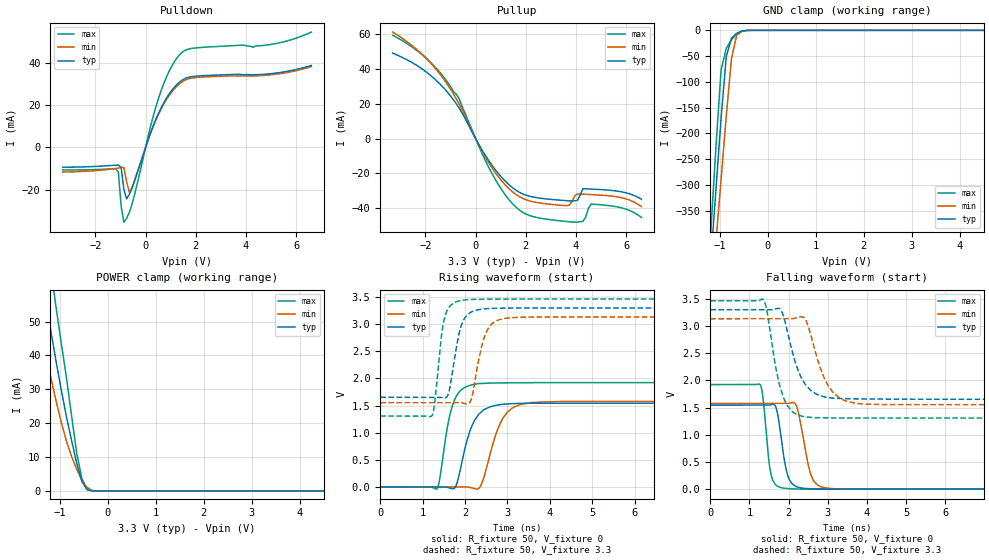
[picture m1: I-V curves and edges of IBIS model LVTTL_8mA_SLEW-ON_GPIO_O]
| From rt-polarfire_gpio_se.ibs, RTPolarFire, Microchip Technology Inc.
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|   Model LVTTL_8mA_SLEW-ON_GPIO_O
[Model]   LVTTL_8mA_SLEW-ON_GPIO_O
Model_type   Output
Polarity   Non-Inverting
Enable   Active-High
Vmeas =   1.65
Cref =   5p
Rref =   1M
|   typ   min   max
C_comp_pullup   2.605e-12   2.605e-12   2.76e-12
C_comp_pulldown  2.605e-12   2.605e-12   2.76e-12
[Temperature Range]  25C   125C   -55C
[Voltage Range]  3.3   3.135   3.465
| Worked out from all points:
|   slope of the pulldown table from 0 to 0.495 V, typ, clamps not added: 31.7 ohm
|   slope of the pullup table from 0 to 0.495 V, typ, clamps not added: 41.2 ohm
|   GND clamp passes 1 mA (typ) near -0.51 V on its own axis
|   POWER clamp passes 1 mA (typ) near -0.46 V on its own axis
|   rising waveform, R_fixture 50, V_fixture 0: 20-80 % time 346ps typ, 395ps min, 271ps max; typ from 0 V to 1.55 V
|   rising waveform, R_fixture 50, V_fixture 3.3: 20-80 % time 236ps typ, 265ps min, 183ps max; typ from 1.65 V to 3.3 V
|   falling waveform, R_fixture 50, V_fixture 0: 20-80 % time 203ps typ, 256ps min, 156ps max; typ from 1.55 V to 0 V
|   falling waveform, R_fixture 50, V_fixture 3.3: 20-80 % time 432ps typ, 471ps min, 341ps max; typ from 3.3 V to 1.65 V
[GND Clamp]
| Voltage   I(typ)   I(min)   I(max)
-3.3V     -3.213A    -2.953A    -3.676A
-1.191V   -450mA     -534.3mA   -393.2mA
-1.083V   -310.2mA   -411.6mA   -227.5mA
-974.5mV  -170.4mA   -288.9mA   -76.97mA
-866.2mV  -50.48mA   -166.3mA   -34.78mA
-758mV    -15.08mA   -54.7mA    -18.33mA
-649.7mV  -5.883mA   -9.683mA   -6.874mA
-541.4mV  -1.389mA   -1.864mA   -1.426mA
-324.8mV  -3.553uA   -16.68uA   -1.172uA
6.6V      0A         0A         0A
[POWER Clamp]
| Voltage   I(typ)   I(min)   I(max)
-3.3V     320.3mA    256.6mA    387.1mA
-1.624V   89.11mA    65.97mA    116.9mA
-1.408V   67.23mA    48.87mA    90.32mA
-1.299V   57.08mA    41.04mA    77.84mA
-1.191V   47.51mA    33.68mA    65.79mA
-1.083V   38.51mA    26.79mA    54.52mA
-866.2mV  22.14mA    14.9mA     33.75mA
-649.7mV  8.213mA    6.429mA    11.19mA
-541.4mV  2.791mA    3.18mA     3.642mA
-433.1mV  359.8uA    981.3uA    499.4uA
-216.6mV  159.8nA    8.88uA     59.07nA
6.6V      0A         0A         0A
[Pullup]
| Voltage   I(typ)   I(min)   I(max)
-3.3V     49.01mA    61.08mA    59.23mA
-1.841V   36.8mA     44.17mA    44.41mA
-758mV    19.77mA    22.59mA    25.23mA
618.8mV   -14.64mA   -16.01mA   -19.11mA
1.238V    -25.28mA   -27.44mA   -33.37mA
1.753V    -30.9mA    -33.39mA   -41.12mA
3.625V    -35.67mA   -38.52mA   -47.62mA
4.058V    -35.49mA   -31.76mA   -47.93mA
4.275V    -28.78mA   -31.92mA   -47.51mA
4.599V    -29mA      -32.17mA   -37.61mA
5.79V     -30.53mA   -33.88mA   -39.68mA
6.6V      -34.85mA   -39.01mA   -45.28mA
[Pulldown]
| Voltage   I(typ)   I(min)   I(max)
-3.3V     -9.313mA   -11.56mA   -10.59mA
-1.191V   -8.379mA   -9.941mA   -9.988mA
-1.083V   -8.301mA   -9.731mA   -11.63mA
-974.5mV  -9.371mA   -9.502mA   -27.6mA
-866.2mV  -19.57mA   -9.359mA   -35.26mA
-758mV    -24.21mA   -15.94mA   -33.52mA
-649.7mV  -22.21mA   -21.08mA   -30.78mA
515.6mV   16.17mA    15.64mA    23.21mA
1.341V    30.74mA    29.91mA    43.59mA
1.959V    33.59mA    32.92mA    46.9mA
5.141V    35.03mA    34.49mA    48.92mA
6.6V      38.71mA    38.17mA    54.44mA
[Ramp]
dV/dt_r   0.927346/0.346344n  0.946255/0.395245n  1.15407/0.270643n
dV/dt_f   0.987567/0.432188n  0.948706/0.471307n  1.29419/0.341378n
R_load = 50
[Rising Waveform]
R_fixture = 50
V_fixture = 0
V_fixture_min = 0
V_fixture_max = 0
| Time   V(typ)   V(min)   V(max)
0s        62.35nV    86.47nV    169.2nV
1.341ns   927uV      524.7uV    -31.51mV
1.603ns   -11.81mV   627.2uV    1.19V
1.712ns   -34.88mV   669.8uV    1.527V
1.801ns   52.34mV    704.6uV    1.682V
2.192ns   1.177V     -24.92mV   1.891V
2.379ns   1.382V     37.41mV    1.908V
2.906ns   1.526V     1.285V     1.92V
3.367ns   1.542V     1.531V     1.923V
10ns      1.546V     1.577V     1.923V
[Rising Waveform]
R_fixture = 50
V_fixture = 3.3
V_fixture_min = 3.135
V_fixture_max = 3.465
| Time   V(typ)   V(min)   V(max)
0s        1.654V     1.554V     1.308V
1.219ns   1.654V     1.554V     1.316V
1.277ns   1.654V     1.554V     1.511V
1.509ns   1.64V      1.555V     3.094V
1.624ns   1.77V      1.555V     3.316V
1.808ns   2.634V     1.555V     3.421V
2.128ns   3.218V     1.582V     3.458V
2.493ns   3.287V     2.843V     3.464V
2.888ns   3.298V     3.101V     3.465V
10ns      3.3V       3.135V     3.465V
[Falling Waveform]
R_fixture = 50
V_fixture = 0
V_fixture_min = 0
V_fixture_max = 0
| Time   V(typ)   V(min)   V(max)
0s        1.546V     1.577V     1.923V
1.278ns   1.546V     1.577V     1.918V
1.559ns   1.554V     1.577V     247.9mV
1.677ns   1.508V     1.577V     75.12mV
1.795ns   1.029V     1.577V     29.68mV
2.088ns   100.2mV    1.594V     5.404mV
2.229ns   38.44mV    1.47V      2.652mV
2.57ns    6.707mV    265.9mV    552.5uV
2.836ns   2.188mV    41.34mV    532.7uV
10ns      749.4nV    5.079uV    113.4nV
[Falling Waveform]
R_fixture = 50
V_fixture = 3.3
V_fixture_min = 3.135
V_fixture_max = 3.465
| Time   V(typ)   V(min)   V(max)
0s        3.3V       3.135V     3.465V
1.362ns   3.299V     3.134V     3.482V
1.449ns   3.299V     3.134V     3.274V
1.723ns   3.328V     3.134V     2.056V
1.856ns   3.211V     3.134V     1.707V
2.339ns   2.035V     3.171V     1.341V
2.468ns   1.893V     3.063V     1.327V
3ns       1.687V     1.917V     1.309V
3.492ns   1.663V     1.613V     1.309V
10ns      1.654V     1.554V     1.308V
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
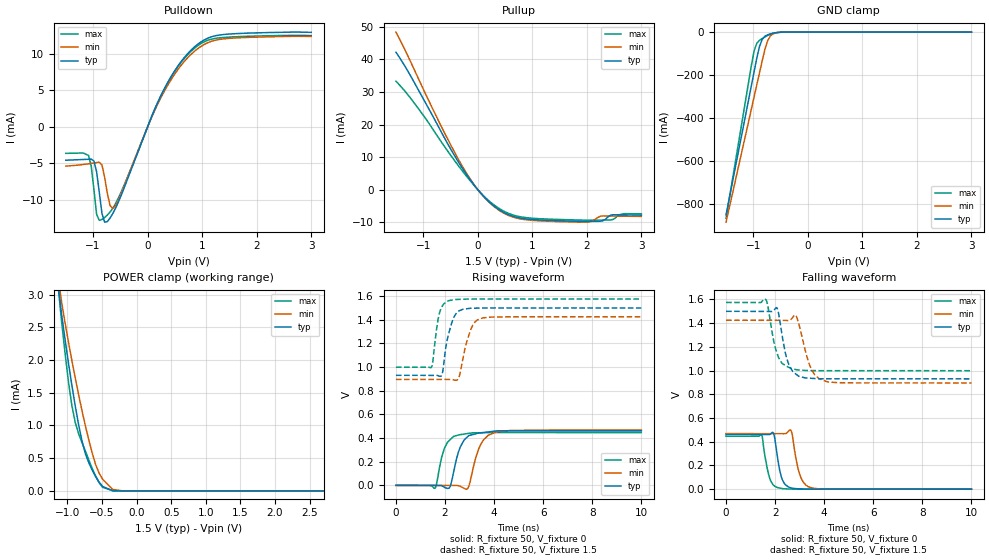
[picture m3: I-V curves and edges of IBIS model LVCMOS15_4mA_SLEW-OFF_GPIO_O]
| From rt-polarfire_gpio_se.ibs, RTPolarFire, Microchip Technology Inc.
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|   Model LVCMOS15_4mA_SLEW-OFF_GPIO_O
[Model]   LVCMOS15_4mA_SLEW-OFF_GPIO_O
Model_type   Output
Polarity   Non-Inverting
Enable   Active-High
Vmeas =   0.75
Cref =   5p
Rref =   1M
|   typ   min   max
C_comp_pullup   2.605e-12   2.605e-12   2.76e-12
C_comp_pulldown  2.605e-12   2.605e-12   2.76e-12
[Temperature Range]  25C   125C   -55C
[Voltage Range]  1.5   1.425   1.575
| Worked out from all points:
|   slope of the pulldown table from 0 to 0.225 V, typ, clamps not added: 56.6 ohm
|   slope of the pullup table from 0 to 0.225 V, typ, clamps not added: 56.5 ohm
|   GND clamp passes 1 mA (typ) near -0.52 V on its own axis
|   POWER clamp passes 1 mA (typ) near -0.84 V on its own axis
|   rising waveform, R_fixture 50, V_fixture 0: 20-80 % time 409ps typ, 449ps min, 359ps max; typ from 0 V to 0.461 V
|   rising waveform, R_fixture 50, V_fixture 1.5: 20-80 % time 336ps typ, 390ps min, 240ps max; typ from 0.93 V to 1.5 V
|   falling waveform, R_fixture 50, V_fixture 0: 20-80 % time 246ps typ, 301ps min, 255ps max; typ from 0.461 V to 0 V
|   falling waveform, R_fixture 50, V_fixture 1.5: 20-80 % time 356ps typ, 447ps min, 362ps max; typ from 1.5 V to 0.93 V
[GND Clamp]
| Voltage   I(typ)   I(min)   I(max)
-1.5V     -849.7mA   -884.3mA   -866.2mA
-1.034V   -246.6mA   -355.8mA   -152.2mA
-984.4mV  -183.1mA   -300.1mA   -86.85mA
-935.2mV  -119.9mA   -244.3mA   -51.18mA
-885.9mV  -66.33mA   -188.6mA   -38.3mA
-836.7mV  -33.59mA   -133mA     -29.88mA
-787.5mV  -19.44mA   -80.26mA   -22.39mA
-738.3mV  -12.87mA   -40.96mA   -15.82mA
-689.1mV  -8.545mA   -18.39mA   -10.35mA
-590.6mV  -2.947mA   -3.965mA   -3.201mA
-393.7mV  -37.64uA   -97.05uA   -25.54uA
3V        0A         0A         0A
[POWER Clamp]
| Voltage   I(typ)   I(min)   I(max)
-1.5V     10.9mA     9.514mA    12.44mA
-1.181V   3.55mA     3.619mA    3.648mA
-1.083V   2.694mA    2.882mA    2.583mA
-984.4mV  1.956mA    2.276mA    1.667mA
-935.2mV  1.615mA    1.995mA    1.306mA
-885.9mV  1.297mA    1.724mA    1.047mA
-738.3mV  562.1uA    988.5uA    604.8uA
-590.6mV  217.4uA    399.3uA    223.5uA
-492.2mV  69.4uA     180.6uA    55.95uA
-344.5mV  1.546uA    22.26uA    2.965uA
-196.9mV  138.9nA    703.2nA    3.319nA
3V        0A         0A         0A
[Pullup]
| Voltage   I(typ)   I(min)   I(max)
-1.5V     42.22mA    48.41mA    33.32mA
-1.083V   30.48mA    33.93mA    24.78mA
-344.5mV  8.198mA    8.976mA    7.117mA
0V        -138.7nA   6.972uA    19.76uA
328.1mV   -5.411mA   -5.582mA   -5.058mA
656.2mV   -8.252mA   -8.491mA   -7.836mA
1.078V    -9.265mA   -9.527mA   -8.873mA
1.992V    -9.771mA   -9.982mA   -9.385mA
2.238V    -9.714mA   -8.228mA   -9.368mA
2.435V    -7.83mA    -8.102mA   -9.304mA
2.681V    -7.759mA   -8.159mA   -7.381mA
3V        -7.819mA   -8.223mA   -7.437mA
[Pulldown]
| Voltage   I(typ)   I(min)   I(max)
-1.5V     -4.58mA    -5.384mA   -3.635mA
-1.083V   -4.447mA   -5.071mA   -3.924mA
-984.4mV  -4.677mA   -4.965mA   -8.591mA
-935.2mV  -6.154mA   -4.907mA   -12.01mA
-836.7mV  -11.89mA   -5.226mA   -12.7mA
-787.5mV  -13.08mA   -6.95mA    -12.44mA
-689.1mV  -12.52mA   -10.78mA   -11.69mA
-590.6mV  -11.2mA    -10.83mA   -10.57mA
234.4mV   4.121mA    3.858mA    4.109mA
843.8mV   10.86mA    10.26mA    10.68mA
1.359V    12.63mA    12.03mA    12.24mA
3V        12.96mA    12.41mA    12.52mA
[Ramp]
dV/dt_r   0.276675/0.408785n  0.281298/0.448932n  0.26773/0.358544n
dV/dt_f   0.341778/0.356073n  0.317434/0.446663n  0.345465/0.361764n
R_load = 50
[Rising Waveform]
R_fixture = 50
V_fixture = 0
V_fixture_min = 0
V_fixture_max = 0
| Time   V(typ)   V(min)   V(max)
0s        19.64nV    51.11nV    26.19nV
1.589ns   -750uV     -478.5uV   -25.07mV
1.871ns   -3.997mV   -563.5uV   242.9mV
2.18ns    -19.84mV   -656.5uV   380.3mV
2.599ns   311.7mV    -6.501mV   428.1mV
2.934ns   413.7mV    -23.14mV   438.6mV
3.439ns   443.8mV    340mV      444.7mV
3.771ns   452mV      425mV      445.6mV
4.102ns   460.3mV    452mV      446.5mV
10ns      461.1mV    468.8mV    446.2mV
[Rising Waveform]
R_fixture = 50
V_fixture = 1.5
V_fixture_min = 1.425
V_fixture_max = 1.575
| Time   V(typ)   V(min)   V(max)
0s        930.4mV    895.9mV    999.2mV
1.439ns   929.7mV    895.4mV    996.6mV
1.491ns   929.6mV    895.4mV    1.03V
1.709ns   928.2mV    895.3mV    1.393V
1.868ns   932.1mV    895.3mV    1.509V
2.147ns   1.279V     895.2mV    1.562V
2.546ns   1.471V     903.6mV    1.572V
3.01ns    1.497V     1.295V     1.575V
3.41ns    1.499V     1.408V     1.575V
10ns      1.5V       1.425V     1.575V
[Falling Waveform]
R_fixture = 50
V_fixture = 0
V_fixture_min = 0
V_fixture_max = 0
| Time   V(typ)   V(min)   V(max)
0s        461.1mV    468.8mV    446.2mV
1.449ns   461.2mV    468.4mV    458.9mV
1.726ns   461.2mV    468.3mV    130.6mV
1.92ns    476.2mV    468.2mV    36.85mV
2.091ns   277.6mV    468.2mV    13.4mV
2.305ns   74.66mV    468.1mV    4.37mV
2.644ns   11.26mV    495.4mV    1.154mV
3.028ns   2.211mV    109.3mV    33.88uV
3.498ns   333.3uV    10.1mV     31.59uV
10ns      219.7nV    4.787uV    -61.69nV
[Falling Waveform]
R_fixture = 50
V_fixture = 1.5
V_fixture_min = 1.425
V_fixture_max = 1.575
| Time   V(typ)   V(min)   V(max)
0s        1.5V       1.425V     1.575V
1.618ns   1.499V     1.424V     1.599V
2.074ns   1.53V      1.424V     1.15V
2.402ns   1.163V     1.424V     1.046V
2.66ns    1.011V     1.435V     1.017V
2.898ns   962.6mV    1.441V     1.006V
3.305ns   937mV      1.11V      1.001V
3.511ns   934.6mV    997.6mV    1V
4.146ns   931.1mV    904.4mV    999.4mV
10ns      930.4mV    895.9mV    999.2mV
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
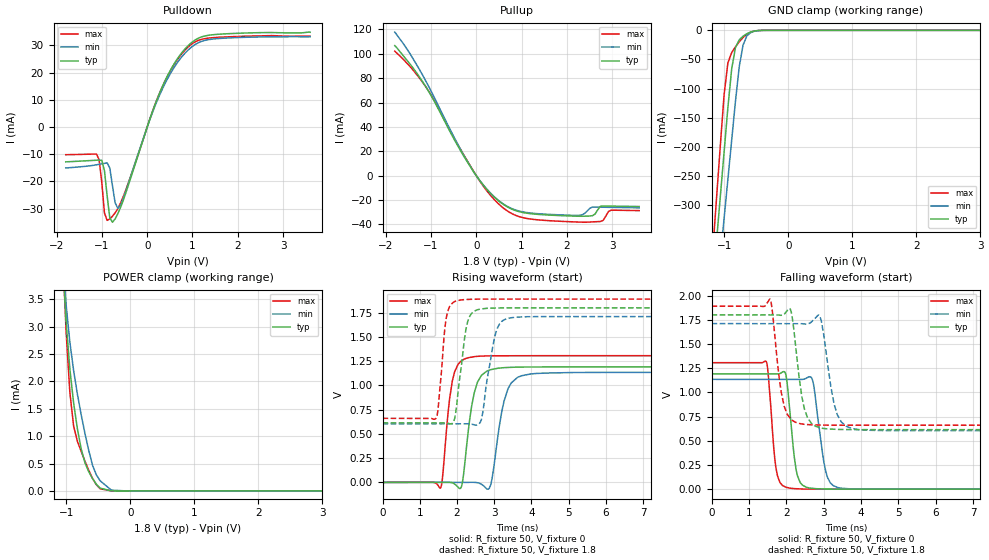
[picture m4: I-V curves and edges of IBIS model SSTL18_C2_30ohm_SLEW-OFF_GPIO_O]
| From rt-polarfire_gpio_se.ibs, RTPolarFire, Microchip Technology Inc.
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|   Model SSTL18_C2_30ohm_SLEW-OFF_GPIO_O
[Model]   SSTL18_C2_30ohm_SLEW-OFF_GPIO_O
Model_type   Output
Polarity   Non-Inverting
Enable   Active-High
Vmeas =   0.9
Cref =   5p
Rref =   50
Vref =   0.9
|   typ   min   max
C_comp_pullup   2.605e-12   2.605e-12   2.76e-12
C_comp_pulldown  2.605e-12   2.605e-12   2.76e-12
[Temperature Range]  25C   125C   -55C
[Voltage Range]  1.8   1.71   1.89
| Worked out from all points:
|   slope of the pulldown table from 0 to 0.27 V, typ, clamps not added: 21.9 ohm
|   slope of the pullup table from 0 to 0.27 V, typ, clamps not added: 21.3 ohm
|   GND clamp passes 1 mA (typ) near -0.52 V on its own axis
|   POWER clamp passes 1 mA (typ) near -0.81 V on its own axis
|   rising waveform, R_fixture 50, V_fixture 0: 20-80 % time 265ps typ, 309ps min, 216ps max; typ from 0 V to 1.19 V
|   rising waveform, R_fixture 50, V_fixture 1.8: 20-80 % time 228ps typ, 277ps min, 167ps max; typ from 0.614 V to 1.8 V
|   falling waveform, R_fixture 50, V_fixture 0: 20-80 % time 189ps typ, 241ps min, 163ps max; typ from 1.19 V to 0 V
|   falling waveform, R_fixture 50, V_fixture 1.8: 20-80 % time 246ps typ, 282ps min, 238ps max; typ from 1.8 V to 0.614 V
[GND Clamp]
| Voltage   I(typ)   I(min)   I(max)
-1.8V     -1.238A    -1.225A    -1.327A
-1.181V   -437.3mA   -523.2mA   -378.1mA
-1.122V   -361mA     -456.2mA   -287.7mA
-1.063V   -284.7mA   -389.3mA   -197.3mA
-1.004V   -208.5mA   -322.4mA   -110.3mA
-945mV    -132.4mA   -255.5mA   -55.69mA
-885.9mV  -66.33mA   -188.6mA   -38.3mA
-826.9mV  -29.63mA   -121.9mA   -28.32mA
-767.8mV  -16.36mA   -62.59mA   -19.64mA
-708.7mV  -10.12mA   -25.53mA   -12.4mA
-649.7mV  -5.882mA   -9.682mA   -6.873mA
3.6V      0A         0A         0A
[POWER Clamp]
| Voltage   I(typ)   I(min)   I(max)
-1.8V     45.61mA    34mA       62.13mA
-1.063V   4.301mA    4.351mA    4.537mA
-1.004V   3.099mA    3.407mA    2.918mA
-945mV    2.226mA    2.718mA    1.799mA
-885.9mV  1.604mA    2.194mA    1.183mA
-767.8mV  765.5uA    1.388mA    720.7uA
-708.7mV  512.4uA    1.046mA    541.9uA
-590.6mV  225.1uA    468.8uA    230.2uA
-472.5mV  50.43uA    184.8uA    39.22uA
-295.3mV  280.4nA    13.94uA    892.7nA
-59.06mV  411.5pA    7.346nA    109nA
3.6V      0A         0A         0A
[Pullup]
| Voltage   I(typ)   I(min)   I(max)
-1.8V     106.7mA    117.8mA    102.2mA
-1.477V   92.27mA    100.9mA    90.12mA
-1.063V   69.91mA    74.11mA    70.07mA
-59.06mV  3.208mA    3.24mA     3.636mA
281.2mV   -13.17mA   -13.05mA   -14.66mA
562.5mV   -22.63mA   -22.32mA   -25.47mA
1.069V    -30.52mA   -30mA      -34.78mA
2.332V    -33.32mA   -32.22mA   -38.16mA
2.568V    -32.85mA   -25.79mA   -37.95mA
2.745V    -25.12mA   -25.85mA   -37.63mA
2.981V    -24.99mA   -26.02mA   -28.31mA
3.6V      -25.33mA   -26.39mA   -28.69mA
[Pulldown]
| Voltage   I(typ)   I(min)   I(max)
-1.8V     -12.79mA   -15.05mA   -10.17mA
-1.122V   -12.21mA   -13.9mA    -9.919mA
-1.004V   -12.25mA   -13.56mA   -20.26mA
-945mV    -16.01mA   -13.37mA   -31.57mA
-885.9mV  -25.24mA   -13.17mA   -34.28mA
-826.9mV  -33.38mA   -15.07mA   -33.72mA
-767.8mV  -34.95mA   -21.58mA   -32.77mA
-708.7mV  -33.74mA   -27.85mA   -31.52mA
-590.6mV  -29.58mA   -28.68mA   -27.97mA
281.2mV   12.77mA    11.99mA    12.74mA
900mV     29.8mA     28.2mA     29.3mA
3.6V      34.77mA    33.12mA    33.31mA
[Ramp]
dV/dt_r   0.714761/0.265307n  0.680569/0.30872n  0.783814/0.215557n
dV/dt_f   0.711324/0.246135n  0.663362/0.281718n  0.737749/0.237642n
R_load = 50
[Rising Waveform]
R_fixture = 50
V_fixture = 0
V_fixture_min = 0
V_fixture_max = 0
| Time   V(typ)   V(min)   V(max)
0s        11.53nV    29.57nV    15.26nV
1.555ns   655.5uV    401.6uV    -58.81mV
1.876ns   -5.567mV   484.5uV    1.048V
2.124ns   -38.77mV   548.5uV    1.255V
2.299ns   515.3mV    593.7uV    1.285V
2.551ns   1.033V     -3.497mV   1.3V
2.869ns   1.157V     -60.24mV   1.305V
3.264ns   1.183V     837.8mV    1.306V
3.631ns   1.189V     1.084V     1.306V
10ns      1.191V     1.134V     1.306V
[Rising Waveform]
R_fixture = 50
V_fixture = 1.8
V_fixture_min = 1.71
V_fixture_max = 1.89
| Time   V(typ)   V(min)   V(max)
0s        614.5mV    604.4mV    660.4mV
1.443ns   613.7mV    604.4mV    664.3mV
1.715ns   613.6mV    604.5mV    1.701V
1.977ns   752.6mV    604.5mV    1.87V
2.244ns   1.585V     604.5mV    1.886V
2.532ns   1.778V     591.4mV    1.889V
2.657ns   1.788V     650.4mV    1.889V
3.043ns   1.798V     1.543V     1.89V
3.337ns   1.799V     1.688V     1.89V
10ns      1.8V       1.71V      1.89V
[Falling Waveform]
R_fixture = 50
V_fixture = 0
V_fixture_min = 0
V_fixture_max = 0
| Time   V(typ)   V(min)   V(max)
0s        1.191V     1.134V     1.306V
1.459ns   1.191V     1.134V     1.32V
1.72ns    1.19V      1.134V     225.7mV
1.993ns   1.171V     1.134V     19.21mV
2.263ns   198.8mV    1.134V     4.598mV
2.541ns   18.93mV    1.147V     1.148mV
2.71ns    8.293mV    1.116V     666.9uV
3.057ns   1.837mV    178.9mV    501.6nV
3.39ns    694.2uV    15.49mV    479.6nV
10ns      1.149uV    4.091uV    42.73nV
[Falling Waveform]
R_fixture = 50
V_fixture = 1.8
V_fixture_min = 1.71
V_fixture_max = 1.89
| Time   V(typ)   V(min)   V(max)
0s        1.8V       1.71V      1.89V
1.563ns   1.799V     1.709V     1.964V
1.865ns   1.796V     1.709V     998.4mV
2.105ns   1.861V     1.709V     731.9mV
2.352ns   1.127V     1.709V     677.9mV
2.571ns   735.1mV    1.707V     667.2mV
2.901ns   635.7mV    1.783V     662.2mV
3.282ns   618.9mV    873.5mV    660.8mV
3.747ns   615.5mV    627.4mV    660.7mV
10ns      614.5mV    604.4mV    660.4mV
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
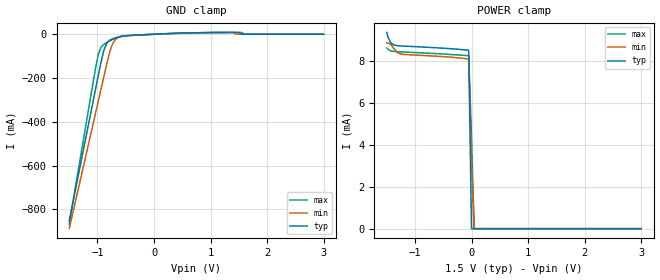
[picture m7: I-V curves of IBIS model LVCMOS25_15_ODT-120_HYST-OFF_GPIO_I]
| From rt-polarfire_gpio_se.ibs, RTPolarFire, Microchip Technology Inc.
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|   Model LVCMOS25_15_ODT-120_HYST-OFF_GPIO_I
[Model]   LVCMOS25_15_ODT-120_HYST-OFF_GPIO_I
Model_type   Input
Vinl =   0.7
Vinh =   1.7
|   typ   min   max
C_comp_pullup   2.605e-12   2.605e-12   2.76e-12
C_comp_pulldown  2.605e-12   2.605e-12   2.76e-12
[Temperature Range]  25C   125C   -55C
[Voltage Range]  1.5   1.425   1.575
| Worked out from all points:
|   GND clamp passes 1 mA (typ) near -0.08 V on its own axis
|   POWER clamp passes 1 mA (typ) near -0.01 V on its own axis
[GND Clamp]
| Voltage   I(typ)   I(min)   I(max)
-1.5V     -852.5mA   -887.8mA   -867.3mA
-1.034V   -249mA     -359.1mA   -153.7mA
-984.4mV  -185.7mA   -303.3mA   -90.69mA
-935.2mV  -123.6mA   -247.5mA   -57.66mA
-885.9mV  -71.93mA   -191.8mA   -45.89mA
-836.7mV  -41.29mA   -136.4mA   -37.9mA
-787.5mV  -28.06mA   -84.83mA   -30.54mA
-738.3mV  -21.49mA   -46.98mA   -23.84mA
-639.8mV  -13.25mA   -15.76mA   -13.59mA
-541.4mV  -8.34mA    -8.622mA   -8.012mA
1.078V    8.054mA    7.636mA    7.874mA
3V        0A         0A         0A
[POWER Clamp]
| Voltage   I(typ)   I(min)   I(max)
-1.5V     9.355mA    8.847mA    8.613mA
-1.477V   9.124mA    8.847mA    8.552mA
-1.427V   8.863mA    8.777mA    8.47mA
-1.378V   8.759mA    8.6mA      8.449mA
-1.329V   8.727mA    8.435mA    8.441mA
-1.28V    8.715mA    8.353mA    8.434mA
-1.181V   8.7mA      8.303mA    8.42mA
-443mV    8.592mA    8.189mA    8.317mA
-49.22mV  8.503mA    8.083mA    8.243mA
0V        0A         3.23mA     4.315mA
46.88mV   0A         0A         0A
3V        0A         0A         0A
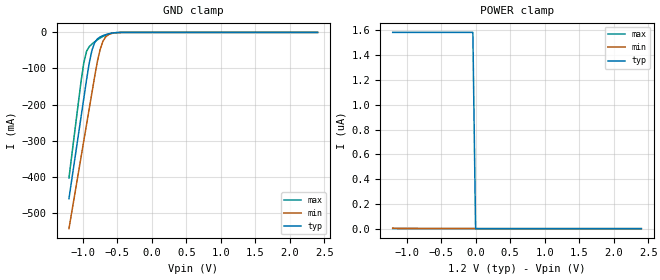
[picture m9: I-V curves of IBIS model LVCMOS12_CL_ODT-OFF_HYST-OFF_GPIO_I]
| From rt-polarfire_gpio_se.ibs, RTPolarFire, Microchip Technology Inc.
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|   Model LVCMOS12_CL_ODT-OFF_HYST-OFF_GPIO_I
[Model]   LVCMOS12_CL_ODT-OFF_HYST-OFF_GPIO_I
Model_type   Input
Vinl =   0.42
Vinh =   0.78
|   typ   min   max
C_comp_pullup   2.605e-12   2.605e-12   2.76e-12
C_comp_pulldown  2.605e-12   2.605e-12   2.76e-12
[Temperature Range]  25C   125C   -55C
[Voltage Range]  1.2   1.14   1.26
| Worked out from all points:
|   GND clamp passes 1 mA (typ) near -0.53 V on its own axis
[GND Clamp]
| Voltage   I(typ)   I(min)   I(max)
-1.2V     -460.9mA   -544.2mA   -403.7mA
-1.024V   -232.8mA   -344.5mA   -134.4mA
-984.4mV  -181.9mA   -299.8mA   -83.61mA
-945mV    -131.1mA   -255.2mA   -52.45mA
-905.6mV  -84.23mA   -210.6mA   -39.32mA
-866.2mV  -48.93mA   -166mA     -32.16mA
-826.9mV  -28.05mA   -121.5mA   -26.09mA
-748.1mV  -12.65mA   -47.05mA   -15.55mA
-708.7mV  -9.067mA   -25.04mA   -11.24mA
-630mV    -4.141mA   -6.61mA    -4.857mA
-393.7mV  -25.22uA   -68.78uA   -17.61uA
2.4V      0A         0A         0A
[POWER Clamp]
| Voltage   I(typ)   I(min)   I(max)
-1.2V     1.585uA    4.233nA    477.6pA
-39.38mV  1.585uA    1.176nA    311.4pA
0V        0A         459pA      0A
2.4V      0A         0A         0A
